! (c) 2009  Infineon Technologies AG, Munich
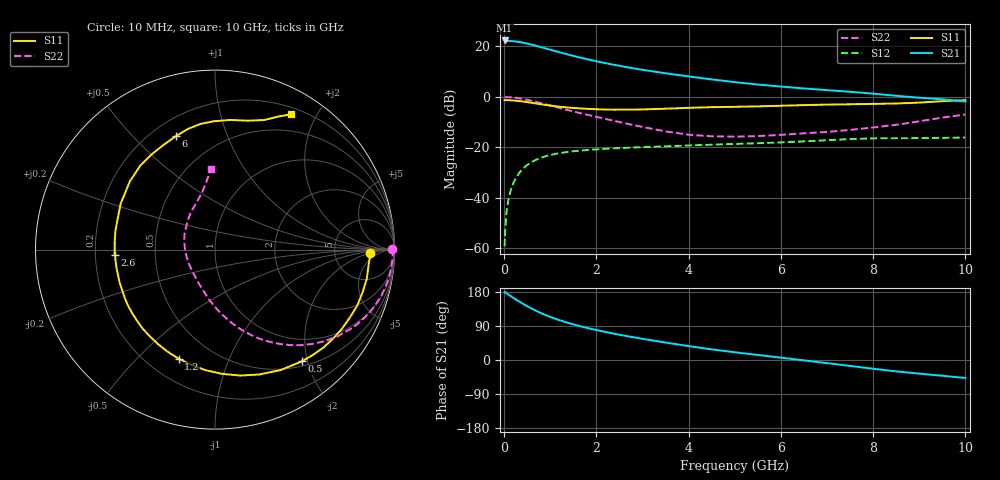
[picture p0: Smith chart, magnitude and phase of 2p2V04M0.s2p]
! Infineon Technologies  Discrete & RF Semiconductors
! BFP420
! VCE =  2.0 V,  IC =  4.0 mA
! Common Emitter S-Parameters:  Nov 2009
# GHz  S  MA  R  50
!  f  S11  S21  S12  S22
! GHz  MAG  ANG  MAG  ANG  MAG  ANG  MAG  ANG
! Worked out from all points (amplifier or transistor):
!   46 points, 10 MHz to 10 GHz, reference 50 ohm
!   highest |S21| = 22.4 dB at 10 MHz (marker M1)
!   |S21| within 3 dB of that: start of sweep to 869.2 MHz
!   unconditionally stable (mu >= 1): 3.227 GHz to end of sweep
!   at 300 MHz: K = 0.08, MSG = 26.3 dB, |S12| = -30.8 dB
!   at 1.7 GHz: K = 0.52, MSG = 18.3 dB, |S12| = -21.2 dB
!   at 10 GHz: K = 1.14, MAG = 4.8 dB, |S12| = -16.1 dB
!   lowest NFmin = 0.61 dB at 900 MHz
!   S11 on the Smith chart (normalised r, x): 10 MHz: 13, -2; 500 MHz: 0.58, -1.91; 1.2 GHz: 0.32, -0.67; 2.6 GHz: 0.28, -0.02; 6 GHz: 0.29, +0.67; 10 GHz: 0.28, +1.67
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0.01  0.8617 -1.1  13.17 179.3  0.0011 106.3  0.9871 0.1
0.02  0.8643 -2.2  12.83 178.6  0.002 85.9  0.9906 -1.2
0.05  0.8605 -5.1  12.86 175.9  0.0051 86.9  0.9899 -3.1
0.1  0.861 -10.9  12.9 172.0  0.01 84.0  0.9865 -6.4
0.25  0.8414 -26.7  12.51 160.0  0.0242 75.9  0.9601 -15.8
0.4  0.8141 -42.1  11.92 149.0  0.0371 67.8  0.9138 -24.7
0.5  0.7894 -52.0  11.4 142.0  0.0447 63.0  0.8765 -30.2
0.6  0.7642 -61.4  10.86 135.4  0.0514 58.5  0.8362 -35.3
0.8  0.7157 -78.7  9.702 123.7  0.0623 50.7  0.7534 -44.3
1  0.6737 -94.5  8.64 113.7  0.0705 44.3  0.6748 -52.0
1.2  0.6406 -108.5  7.686 105.0  0.0768 39.2  0.6042 -58.7
1.4  0.6146 -121.1  6.873 97.4  0.0816 35.0  0.5431 -64.6
1.7  0.5881 -137.7  5.887 87.6  0.0872 30.0  0.4656 -72.2
2.2  0.5623 -160.9  4.673 73.9  0.0939 23.9  0.3664 -83.4
2.6  0.5594 -177.2  3.982 64.4  0.0977 20.1  0.3037 -92.5
3.5  0.5846 154.1  2.942 46.0  0.1049 13.9  0.2071 -116.4
4.5  0.6268 131.5  2.226 28.0  0.113 8.6  0.166 -151.0
5.5  0.6496 116.3  1.763 13.3  0.1208 4.2  0.1673 179.0
6  0.6681 109.2  1.604 6.2  0.1254 2.2  0.177 165.4
7  0.7045 96.7  1.364 -8.3  0.1386 -3.0  0.2022 143.1
8.5  0.741 75.7  1.053 -30.0  0.1518 -15.6  0.28 111.8
10  0.8627 60.8  0.811 -47.4  0.1572 -23.6  0.4483 92.8
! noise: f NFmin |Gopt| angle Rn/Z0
0.9  0.61  0.27  32  0.16
1.8  1.03  0.14  83  0.13
2.4  1.11  0.17  110  0.14
3  1.23  0.2  153  0.11
4  1.42  0.31  -151  0.11
5  1.77  0.38  -123  0.23
6  2.35  0.47  -104  0.33
